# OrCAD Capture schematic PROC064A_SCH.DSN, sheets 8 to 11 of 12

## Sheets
8 09. RGMII ETHERNET PHY 3: size C; title: RGMII ETHERNET PHY 3
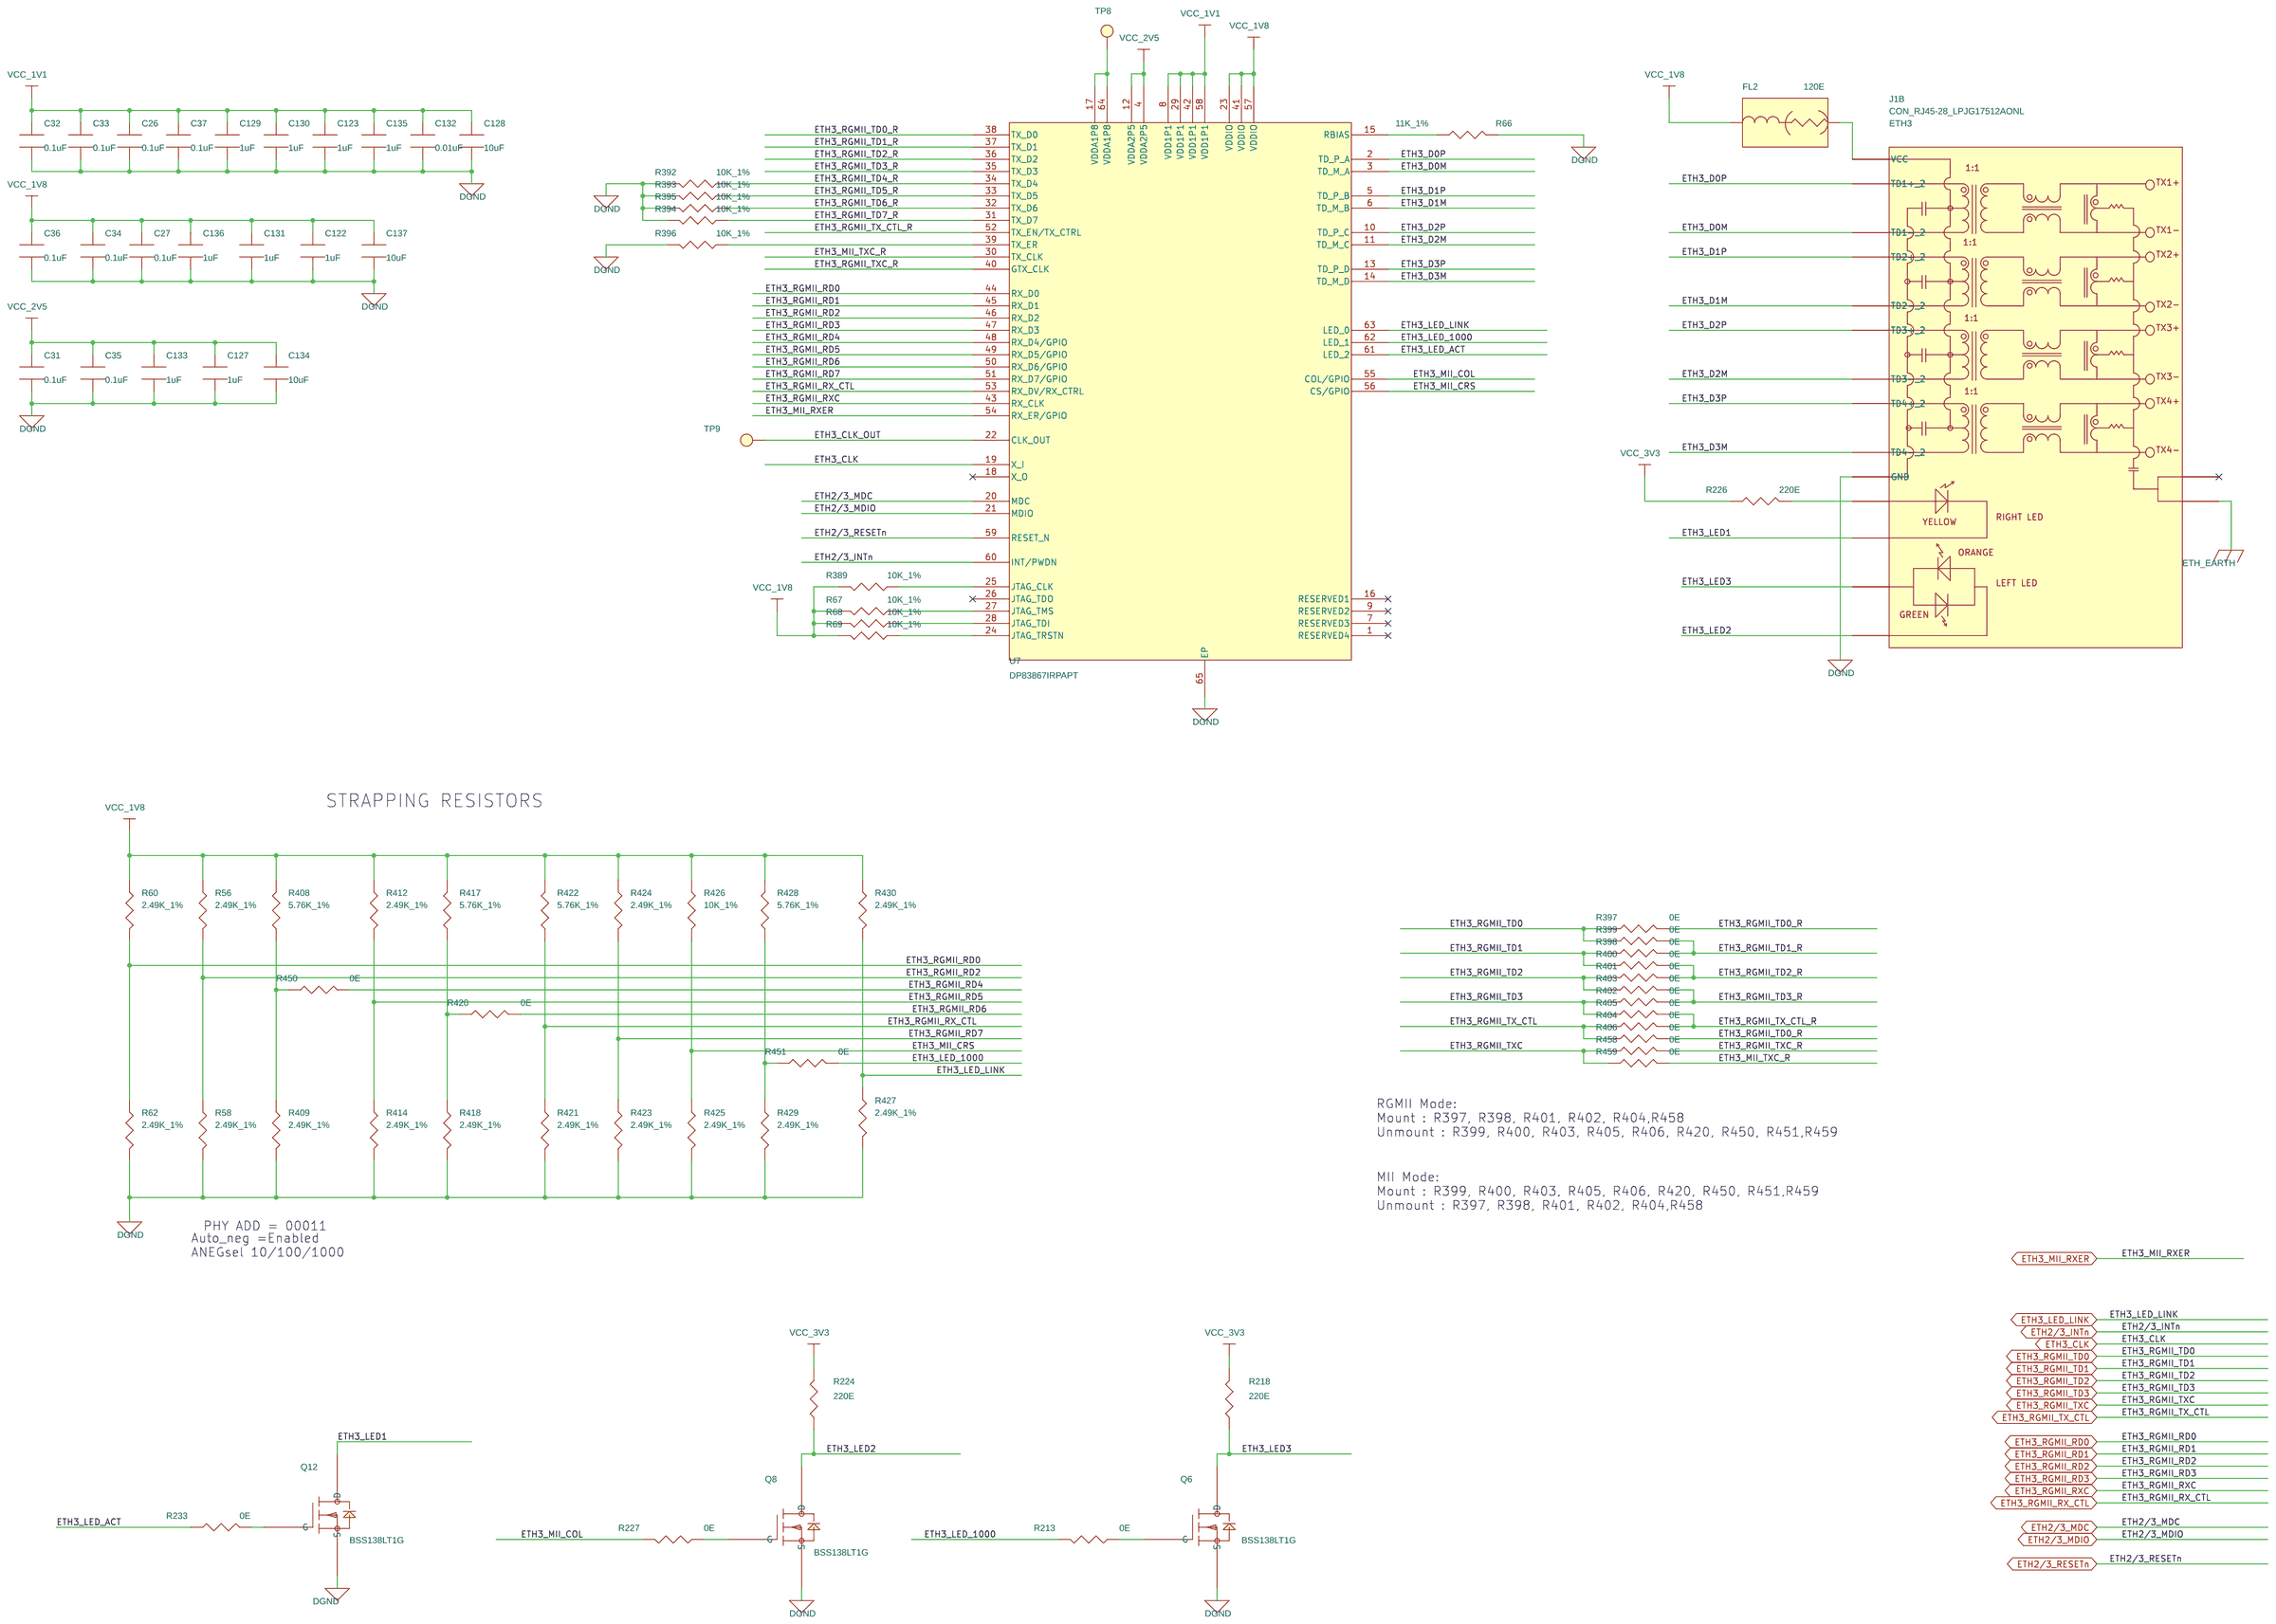
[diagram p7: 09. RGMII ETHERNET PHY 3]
9 10. LED: size C; title: LED
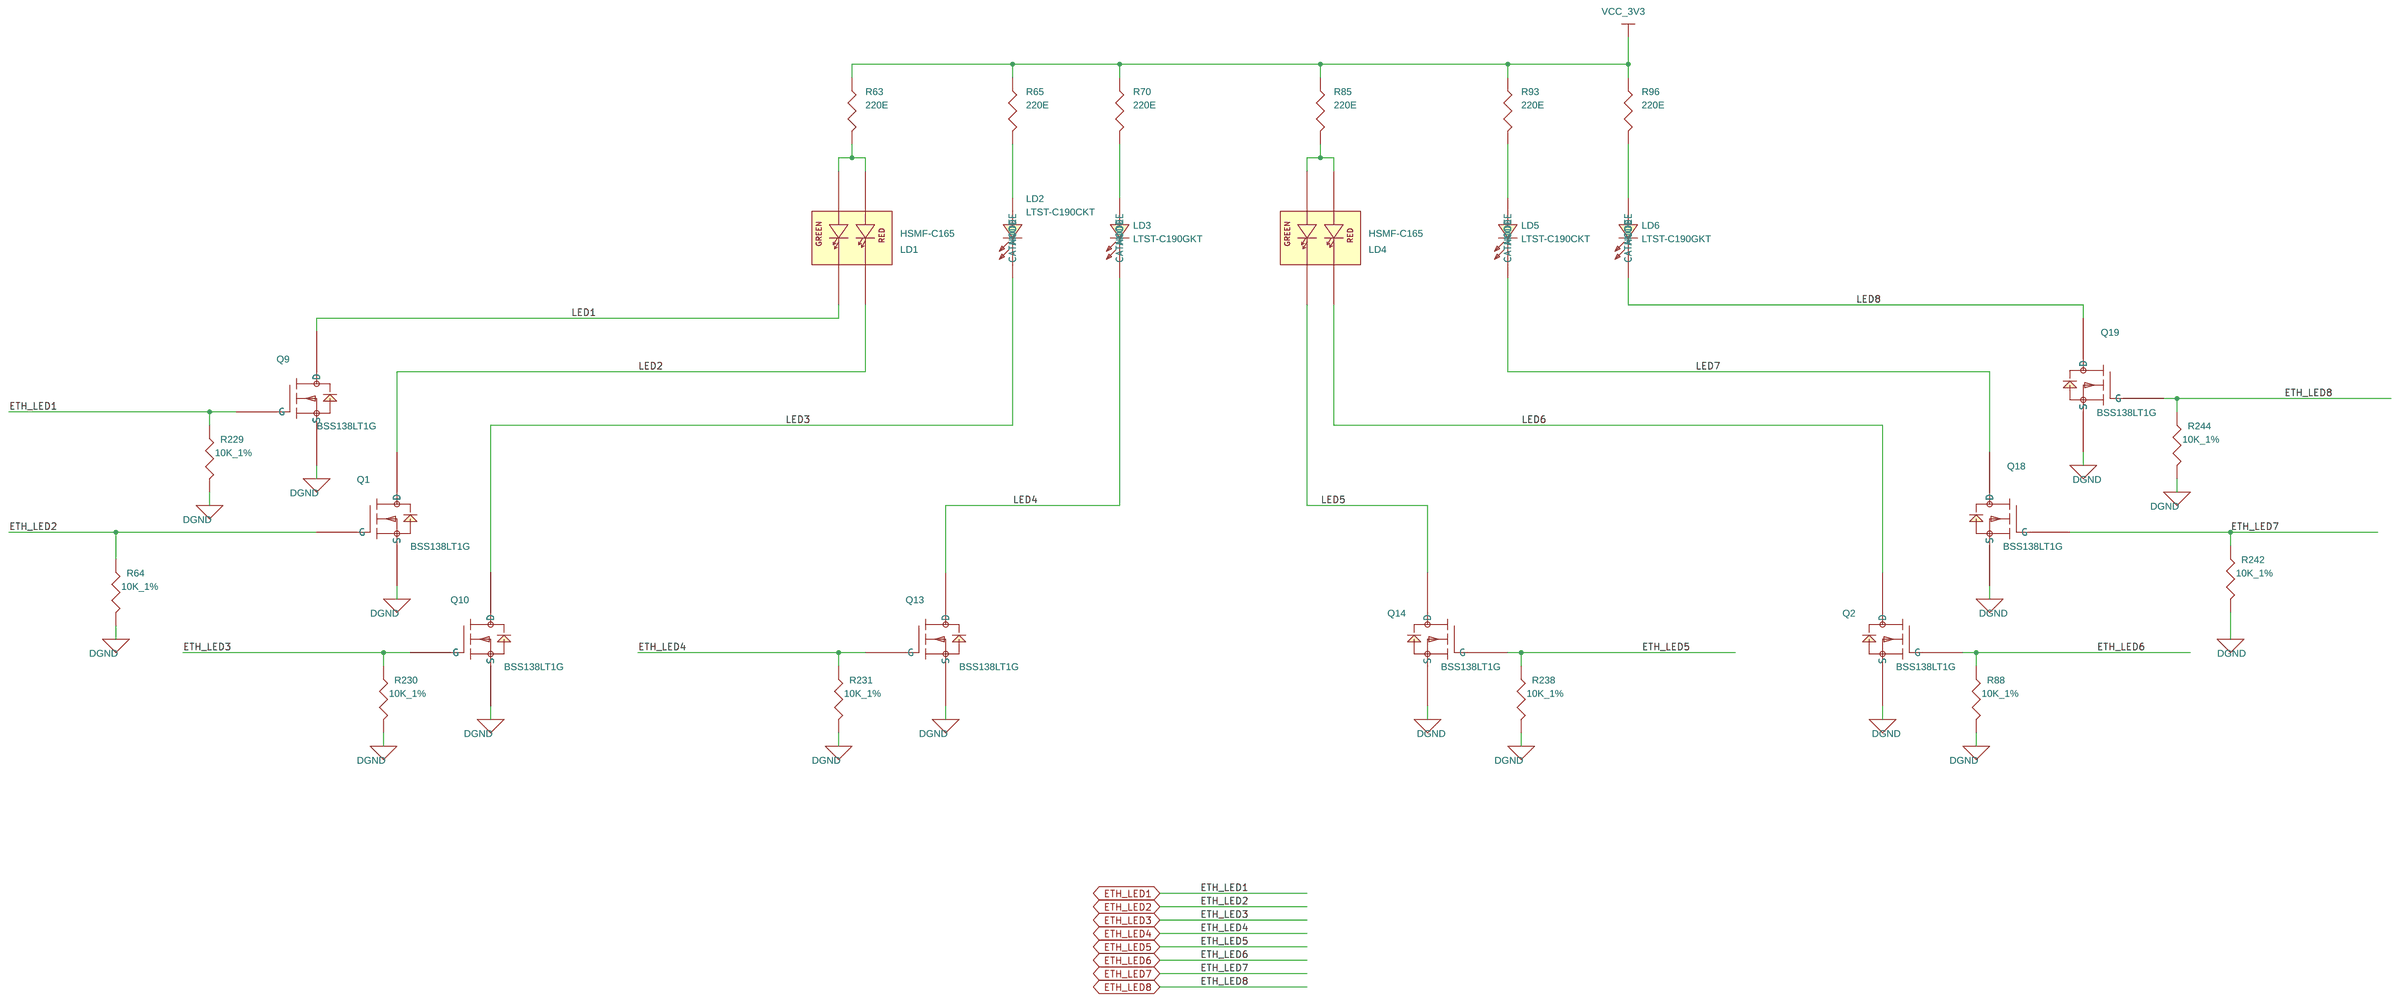
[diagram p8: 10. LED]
10 12. HARDWARE SCHEMATICS: title: HARDWARE SCHEMATICS
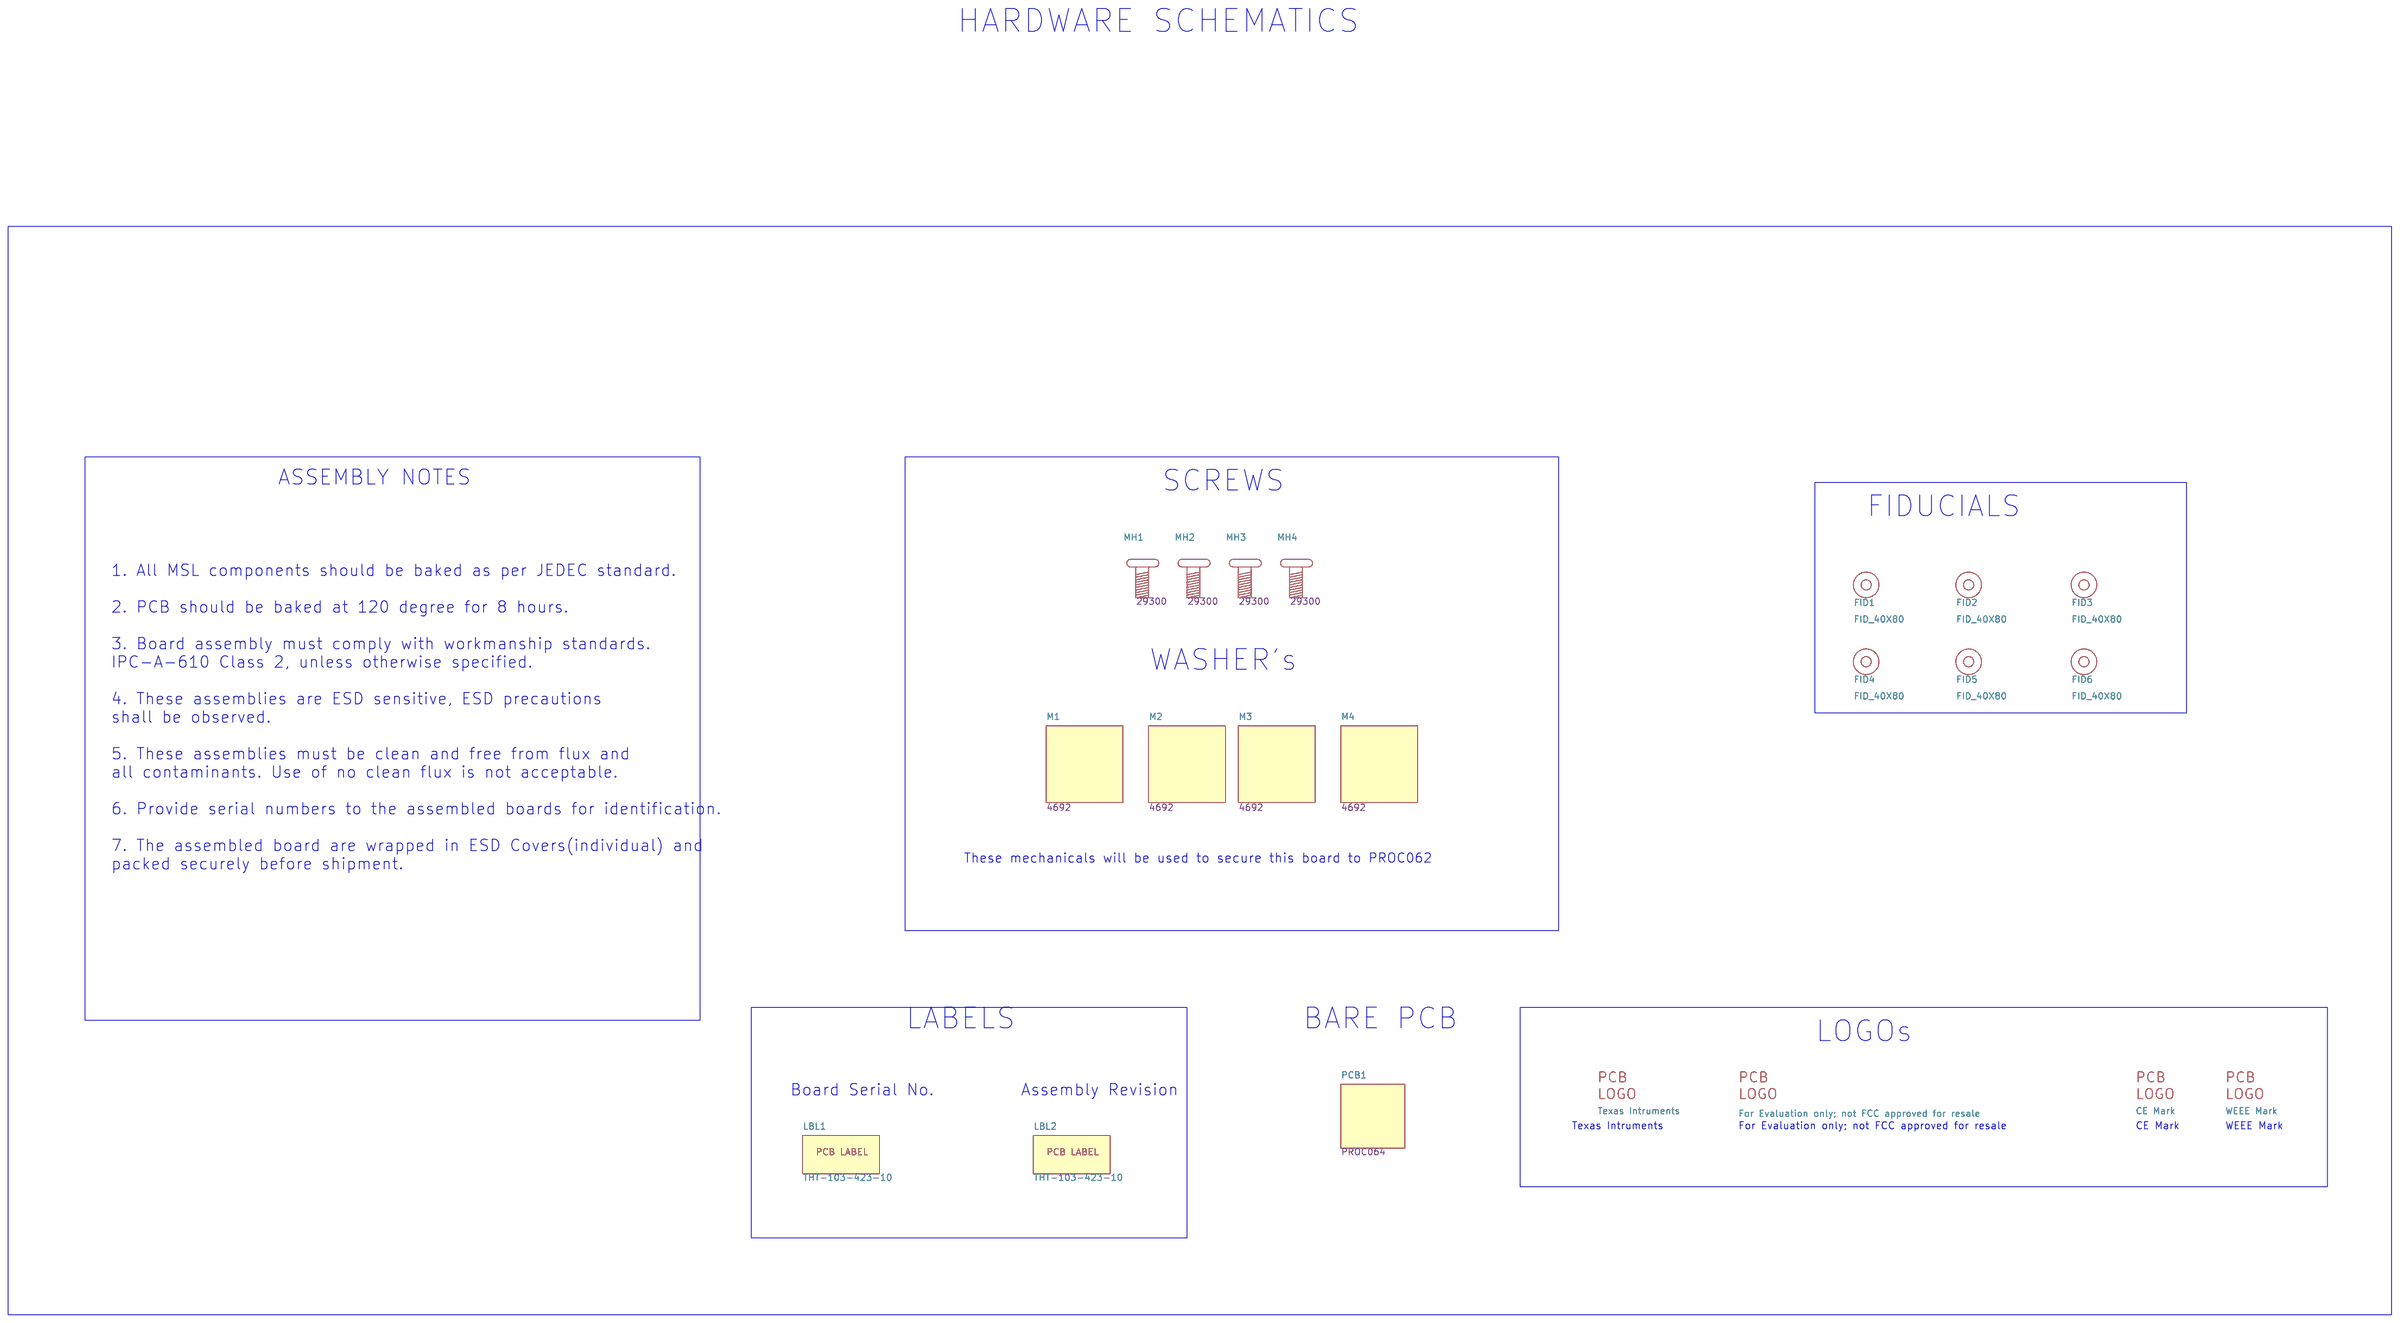
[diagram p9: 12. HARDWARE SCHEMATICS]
11 11. SPI/I2C IOEXPANDER: size C; title: SPI/I2C IOEXPANDER

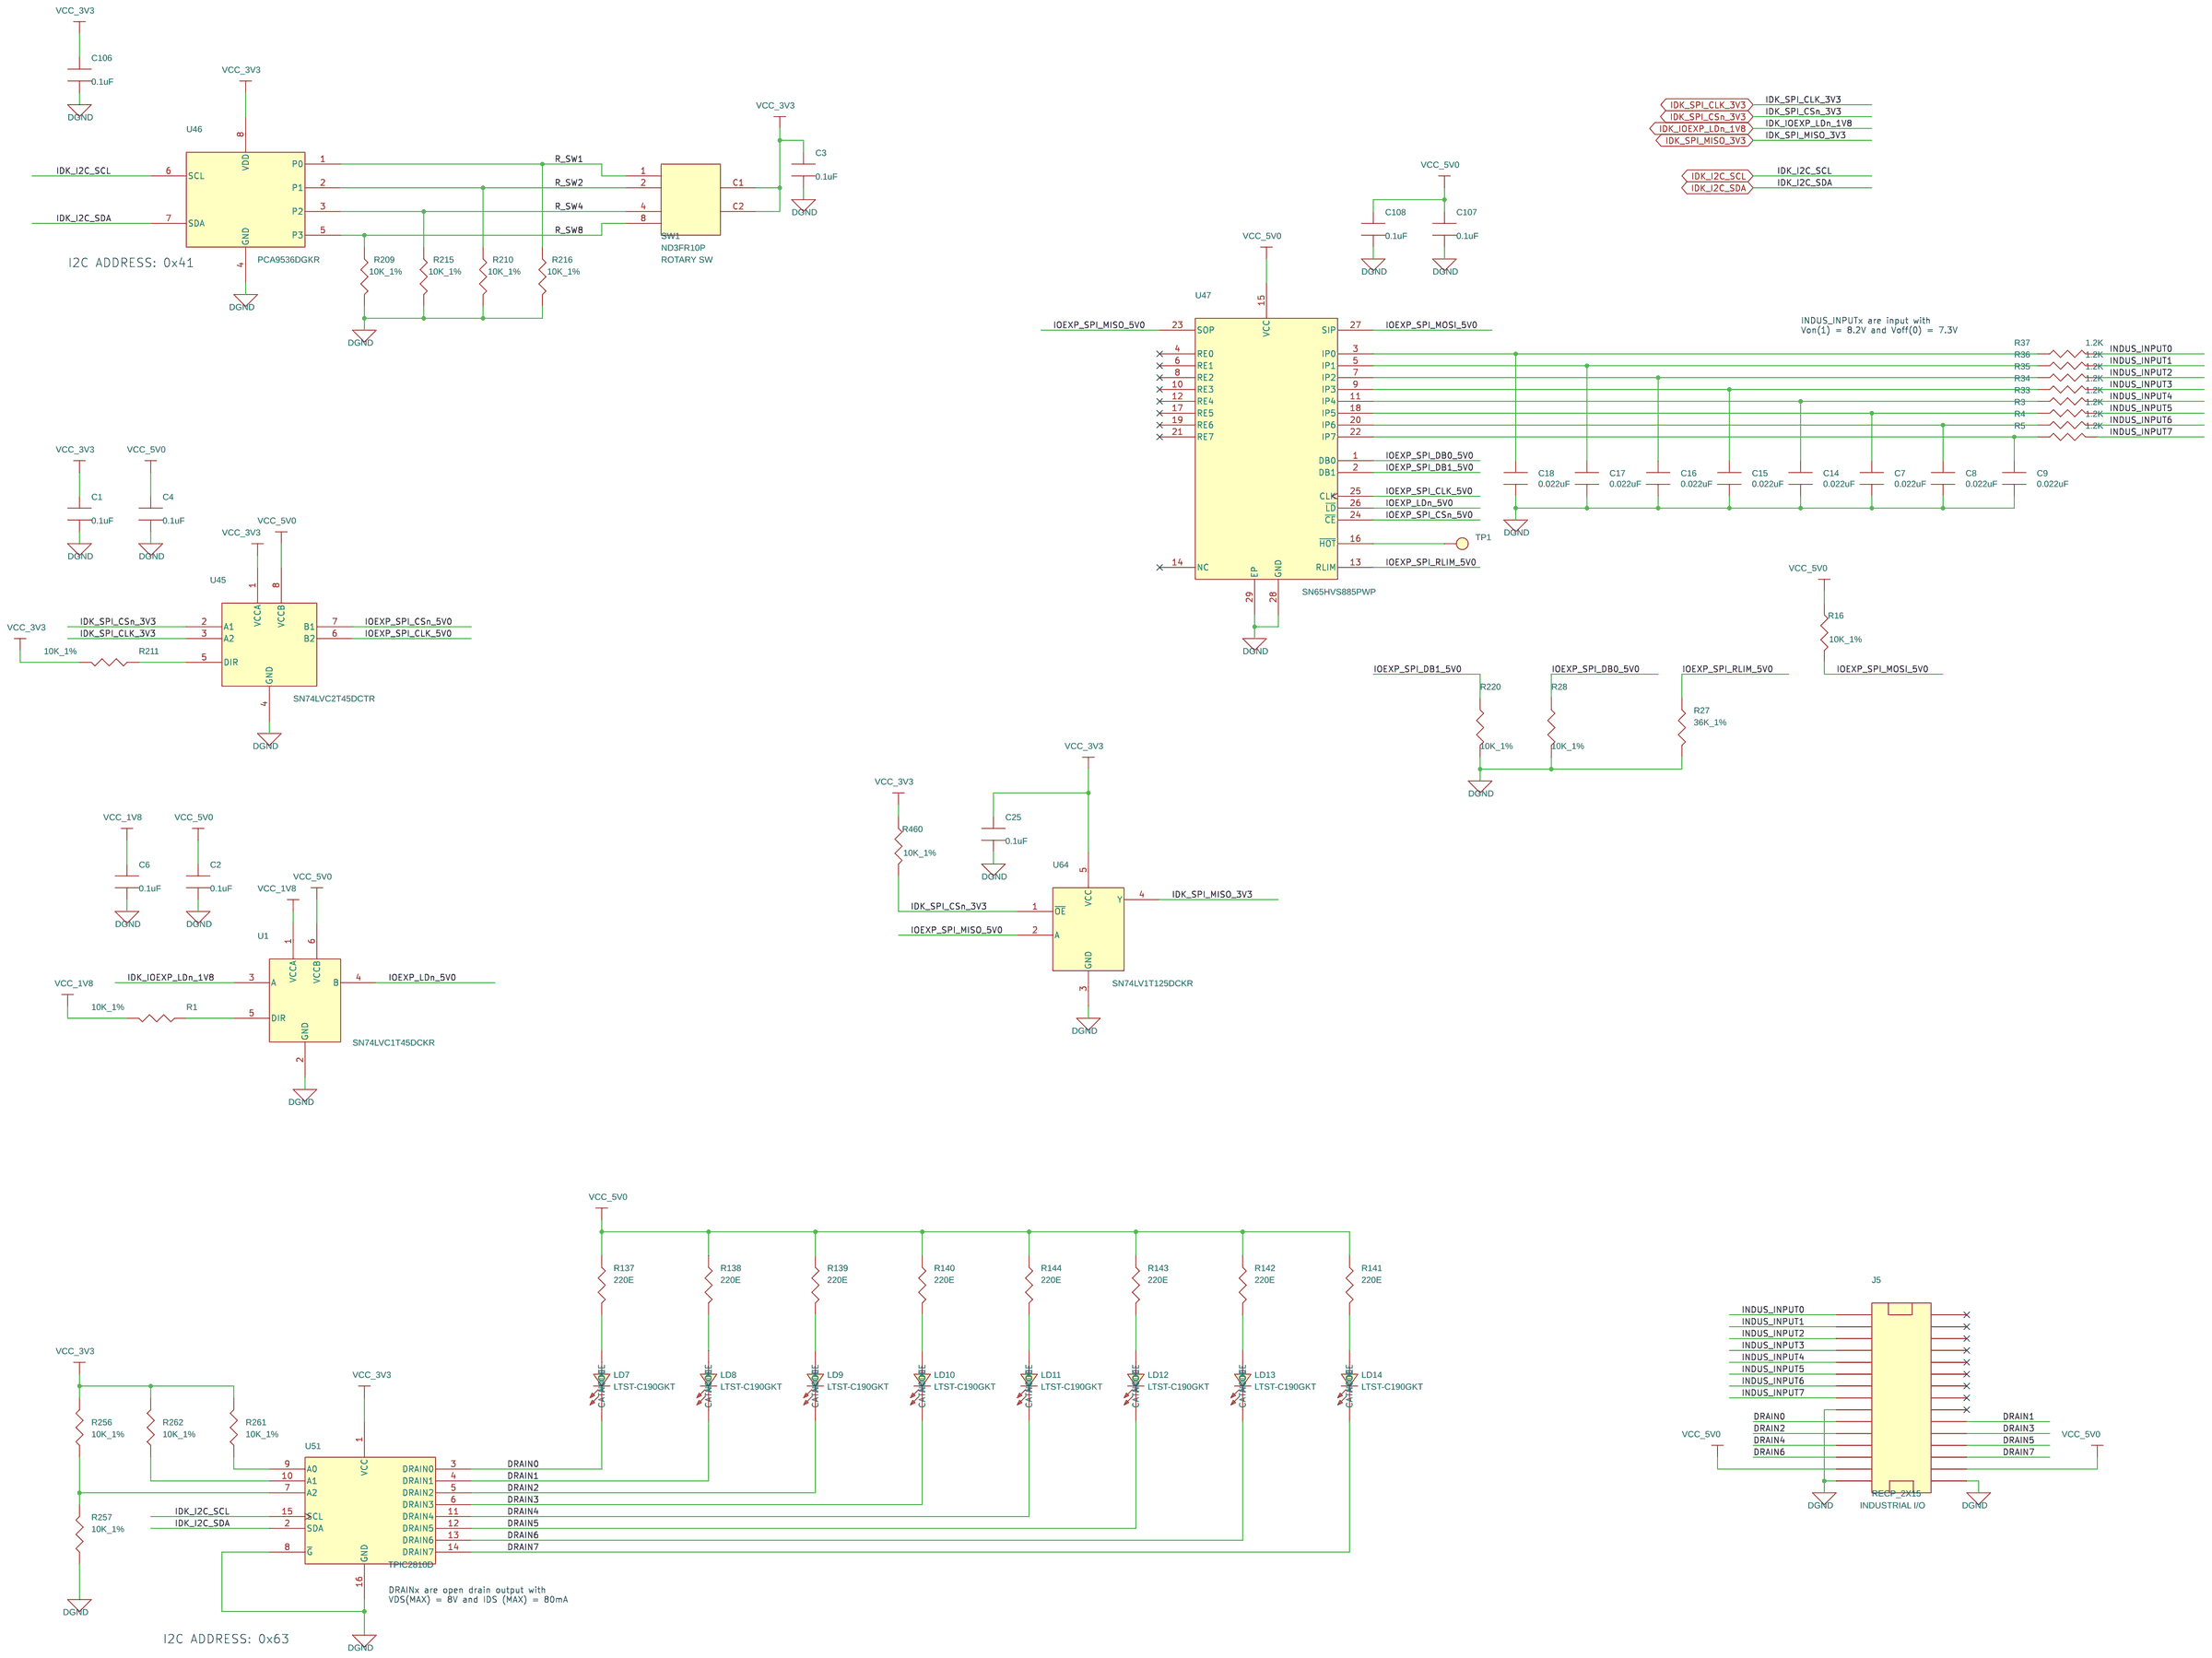
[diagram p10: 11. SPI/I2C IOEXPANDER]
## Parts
sheet 08. RGMII ETHERNET PHY 2
J1  CON_RJ45-28_LPJG17512AONL  [CON_RJ45-28_LPJG17512_S_R_T_25-3]  (sections A,B)
sheet 09. RGMII ETHERNET PHY 3
C26  0.1uF  [CAP0402_0-75]
C27  0.1uF  [CAP0402_0-75]
C31  0.1uF  [CAP0402_0-75]
C32  0.1uF  [CAP0402_0-75]
C33  0.1uF  [CAP0402_0-75]
C34  0.1uF  [CAP0402_0-75]
C35  0.1uF  [CAP0402_0-75]
C36  0.1uF  [CAP0402_0-75]
C37  0.1uF  [CAP0402_0-75]
C122  1uF  [CAP0402_0-75]
C123  1uF  [CAP0402_0-75]
C127  1uF  [CAP0402_0-75]
C128  10uF  [CAP0603_1]
C129  1uF  [CAP0402_0-75]
C130  1uF  [CAP0402_0-75]
C131  1uF  [CAP0402_0-75]
C132  0.01uF  [CAP0402]
C133  1uF  [CAP0402_0-75]
C134  10uF  [CAP0603_1]
C135  1uF  [CAP0402_0-75]
C136  1uF  [CAP0402_0-75]
C137  10uF  [CAP0603_1]
FL2  120E  [EMIFIL_BLM15A_0402_0-6]
Q6  BSS138LT1G  [SOT23-123]
Q8  BSS138LT1G  [SOT23-123]
Q12  BSS138LT1G  [SOT23-123]
R56  2.49K_1%  [RES0402]
R58  2.49K_1%  [RES0402]
R60  2.49K_1%  [RES0402]
R62  2.49K_1%  [RES0402]
R66  11K_1%  [RES0402_0-5]
R67  10K_1%  [RES0402_0-5]
R68  10K_1%  [RES0402_0-5]
R69  10K_1%  [RES0402_0-5]
R213  0E  [RES0402_0-5]
R218  220E  [RES0402_0-5]
R224  220E  [RES0402_0-5]
R226  220E  [RES0402_0-5]
R227  0E  [RES0402_0-5]
R233  0E  [RES0402_0-5]
R389  10K_1%  [RES0402_0-5]
R392  10K_1%  [RES0402_0-5]
R393  10K_1%  [RES0402_0-5]
R394  10K_1%  [RES0402_0-5]
R395  10K_1%  [RES0402_0-5]
R396  10K_1%  [RES0402_0-5]
R397  0E  [RES0402_0-5]
R398  0E  [RES0402_0-5]
R399  0E  [RES0402_0-5]
R400  0E  [RES0402_0-5]
R401  0E  [RES0402_0-5]
R402  0E  [RES0402_0-5]
R403  0E  [RES0402_0-5]
R404  0E  [RES0402_0-5]
R405  0E  [RES0402_0-5]
R406  0E  [RES0402_0-5]
R408  5.76K_1%  [RES0402]
R409  2.49K_1%  [RES0402]
R412  2.49K_1%  [RES0402]
R414  2.49K_1%  [RES0402]
R417  5.76K_1%  [RES0402]
R418  2.49K_1%  [RES0402]
R420  0E  [RES0402_0-5]
R421  2.49K_1%  [RES0402]
R422  5.76K_1%  [RES0402]
R423  2.49K_1%  [RES0402]
R424  2.49K_1%  [RES0402]
R425  2.49K_1%  [RES0402]
R426  10K_1%  [RES0402_0-5]
R427  2.49K_1%  [RES0402]
R428  5.76K_1%  [RES0402]
R429  2.49K_1%  [RES0402]
R430  2.49K_1%  [RES0402]
R450  0E  [RES0402_0-5]
R451  0E  [RES0402_0-5]
R458  0E  [RES0402_0-5]
R459  0E  [RES0402_0-5]
TP8  TP40_SMD  [TP40_SMD]
TP9  TP40_SMD  [TP40_SMD]
U7  DP83867IRPAPT  [EQFP64_19-68_400X400]
sheet 10. LED
LD1  HSMF-C165  [LED4_HSMF-C165_0603_0-5]
LD2  LTST-C190CKT  [LED_0603_0-8]
LD3  LTST-C190GKT  [LED_LTST_0603_0-8]
LD4  HSMF-C165  [LED4_HSMF-C165_0603_0-5]
LD5  LTST-C190CKT  [LED_0603_0-8]
LD6  LTST-C190GKT  [LED_LTST_0603_0-8]
Q1  BSS138LT1G  [SOT23-123]
Q2  BSS138LT1G  [SOT23-123]
Q9  BSS138LT1G  [SOT23-123]
Q10  BSS138LT1G  [SOT23-123]
Q13  BSS138LT1G  [SOT23-123]
Q14  BSS138LT1G  [SOT23-123]
Q18  BSS138LT1G  [SOT23-123]
Q19  BSS138LT1G  [SOT23-123]
R63  220E  [RES0402_0-5]
R64  10K_1%  [RES0402_0-5]
R65  220E  [RES0402_0-5]
R70  220E  [RES0402_0-5]
R85  220E  [RES0402_0-5]
R88  10K_1%  [RES0402_0-5]
R93  220E  [RES0402_0-5]
R96  220E  [RES0402_0-5]
R229  10K_1%  [RES0402_0-5]
R230  10K_1%  [RES0402_0-5]
R231  10K_1%  [RES0402_0-5]
R238  10K_1%  [RES0402_0-5]
R242  10K_1%  [RES0402_0-5]
R244  10K_1%  [RES0402_0-5]
sheet 11. SPI/I2C IOEXPANDER
C1  0.1uF  [CAP0402_0-75]
C2  0.1uF  [CAP0402_0-75]
C3  0.1uF  [CAP0402_0-75]
C4  0.1uF  [CAP0402_0-75]
C6  0.1uF  [CAP0402_0-75]
C7  0.022uF  [CAP0402]
C8  0.022uF  [CAP0402]
C9  0.022uF  [CAP0402]
C14  0.022uF  [CAP0402]
C15  0.022uF  [CAP0402]
C16  0.022uF  [CAP0402]
C17  0.022uF  [CAP0402]
C18  0.022uF  [CAP0402]
C25  0.1uF  [CAP0402_0-75]
C106  0.1uF  [CAP0402_0-75]
C107  0.1uF  [CAP0402_0-75]
C108  0.1uF  [CAP0402_0-75]
J5  RECP_2X15  [RECPT_2X15_66953-015_S_T_8-5]
LD7  LTST-C190GKT  [LED_LTST_0603_0-8]
LD8  LTST-C190GKT  [LED_LTST_0603_0-8]
LD9  LTST-C190GKT  [LED_LTST_0603_0-8]
LD10  LTST-C190GKT  [LED_LTST_0603_0-8]
LD11  LTST-C190GKT  [LED_LTST_0603_0-8]
LD12  LTST-C190GKT  [LED_LTST_0603_0-8]
LD13  LTST-C190GKT  [LED_LTST_0603_0-8]
LD14  LTST-C190GKT  [LED_LTST_0603_0-8]
R1  10K_1%  [RES0402_0-5]
R3  1.2K  [RES0402]
R4  1.2K  [RES0402]
R5  1.2K  [RES0402]
R16  10K_1%  [RES0402_0-5]
R27  36K_1%  [RES0402_0-5]
R28  10K_1%  [RES0402_0-5]
R33  1.2K  [RES0402]
R34  1.2K  [RES0402]
R35  1.2K  [RES0402]
R36  1.2K  [RES0402]
R37  1.2K  [RES0402]
R137  220E  [RES0402_0-5]
R138  220E  [RES0402_0-5]
R139  220E  [RES0402_0-5]
R140  220E  [RES0402_0-5]
R141  220E  [RES0402_0-5]
R142  220E  [RES0402_0-5]
R143  220E  [RES0402_0-5]
R144  220E  [RES0402_0-5]
R209  10K_1%  [RES0402_0-5]
R210  10K_1%  [RES0402_0-5]
R211  10K_1%  [RES0402_0-5]
R215  10K_1%  [RES0402_0-5]
R216  10K_1%  [RES0402_0-5]
R220  10K_1%  [RES0402_0-5]
R256  10K_1%  [RES0402_0-5]
R257  10K_1%  [RES0402_0-5]
R261  10K_1%  [RES0402_0-5]
R262  10K_1%  [RES0402_0-5]
R460  10K_1%  [RES0402_0-5]
SW1  ND3FR10P  [SW10_ND3FR10P_320X300_SMD_5-6]
TP1  TP40_SMD  [TP40_SMD]
U1  SN74LVC1T45DCKR  [SC70-6_1-1]
U45  SN74LVC2T45DCTR  [SSOP8_25-59_120X110]
U46  PCA9536DGKR  [MSOP8_25-59_125X125_1-1]
U47  SN65HVS885PWP  [ETSSOP28_SN65HVS885_390X180_1-2]
U51  TPIC2810D  [SOIC16_1-8]
U64  SN74LV1T125DCKR  [SC70-5_1-1]
sheet 12. HARDWARE SCHEMATICS
FID1  FID_40X80  [FID_40X80]
FID2  FID_40X80  [FID_40X80]
FID3  FID_40X80  [FID_40X80]
FID4  FID_40X80  [FID_40X80]
FID5  FID_40X80  [FID_40X80]
FID6  FID_40X80  [FID_40X80]
LBL1  THT-103-423-10  [NA]
LBL2  THT-103-423-10  [NA]
Logo1  Texas Intruments  [TI_Stacked_Overlay_Small]
Logo2  For Evaluation only; not FCC approved for resale  [FCC_disclaimer]
Logo3  CE Mark  [TI_Stacked_Overlay_Small]
Logo4  WEEE Mark  [TI_Stacked_Overlay_Small]
M1  PLAIN WASHER_M3  [NA]
M2  PLAIN WASHER_M3  [NA]
M3  PLAIN WASHER_M3  [NA]
M4  PLAIN WASHER_M3  [NA]
MH1  PAN HEAD_M2.5 X 4  [NA]
MH2  PAN HEAD_M2.5 X 4  [NA]
MH3  PAN HEAD_M2.5 X 4  [NA]
MH4  PAN HEAD_M2.5 X 4  [NA]
PCB1  AM65x EVM IDK  BARE PCB  [NA]

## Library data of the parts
J1 = CON_RJ45-28_LPJG17512AONL: CON JACK RJ45 28POS REGISTERED FEMALE RA TH; Chkd/date: MANIRAJA/010817; Crtd /date: MANIRAJA/010817; Custom_Duty: 24%; Customs_HS_Code: 85369090; Distributor_name: NA; Distributor_part_number: NA; Height: 25.30MM; Mfr_name: LINK-PP; Mfr_part_number: LPJG17512AONL; Mistral Part No: 150017080001-R; Package: THRU-HOLE; Part_type: CONNECTOR\JACK; Project: TI_SVB_DUT; RoHS: RoHS; TEXT1: ETH2; Temperature: 0°C+70°C; Tolerance: NA; Voltage: NA; Wattage: NA; Weight: NA; Datasheet: Y:\MIS_DATABASE\DATASHEETS\CONNECTORS\LPJG17512AONL.PDF
C1-C4 C6 C25-C27 C31-C37 C106-C108 = CAP: CAP CERAMIC 0.1uF 25V 10% X5R 0402; Chkd/date: MANIRAJA/190220; Crtd /date: ALVY/190220; Custom_Duty: 15%; Customs_HS_Code: 85322990; Distributor_name: DIGIKEY; Distributor_part_number: 311-1697-1-ND; Footprint Path: Y:\MIS_DATABASE\Library\ALTIUM_TOOL\PCB_FOOTPRINTS\Altium_Footprint_Lib.PcbLib; Height: 0.55MM; Library Path: Y:\MIS_DATABASE\Library\ALTIUM_TOOL\SCHEMATICS_PARTS\MS_DISCRETE_Library.schlib; Mfr_name: YAGEO AMERICA; Mfr_part_number: CC0402KRX5R8BB104; Mistral Part No: 120017080016-R; Package: 0402; Part_type: CAPACITORS\CERAMIC; Project: TI_MAXIE_CPB; RoHS: RoHS; Temperature: -55°C+85°C; Tolerance: 10%; Voltage: 25V; Wattage: NA; Weight: 0.65mg; Datasheet: Y:\MIS_DATABASE\DATASHEETS\CAPACITORS\YACC-X5R.PDF
C122 C123 C127 C129-C131 C133 C135 C136 = CAP: CAP CERAMIC 1uF 16V 10% X5R 0402; Chkd/date: MANIRAJA/210817; Crtd /date: MANIRAJA/210817; Custom_Duty: 15%; Customs_HS_Code: 85322990; Distributor_name: DIGIKEY; Distributor_part_number: 587-3709-1-ND; Height: 0.55MM; Mfr_name: TAIYO YUDEN; Mfr_part_number: EMK105BJ105KVHF; Mistral Part No: 120011050002-R; Package: 0402; Part_type: CAPACITORS\CERAMIC; Project: TI_RF_DC CARD; RoHS: RoHS; Temperature: -55°C+85°C; Tolerance: 10%; Voltage: 16V; Wattage: NA; Weight: 0.65mg; Datasheet: Y:\MIS_DATABASE\DATASHEETS\CAPACITORS\EMK105BJ105KVHF.PDF
C128 C134 C137 = CAP: CAP CERAMIC 10uF 25V 20% X5R 0603; Chkd/date: MANIRAJA/130617; Crtd /date: MUDDU/130810; Custom_Duty: 15%; Customs_HS_Code: 85322990; Distributor_name: DIGIKEY; Distributor_part_number: 490-7202-1-ND; Height: 0.90MM; Mfr_name: MURATA; Mfr_part_number: GRM188R61E106MA73D; Mistral Part No: 120010080005-R; Package: 0603; Part_type: CAPACITORS\CERAMIC; Project: PB_BUGBASE; RoHS: RoHS; Temperature: -55°C+85°C; Tolerance: 20%; Voltage: 25V; Wattage: NA; Weight: 6.3mg; Datasheet: Y:\MIS_DATABASE\DATASHEETS\CAPACITORS\MURATA_CMCC.PDF
C132 = CAP: CAP CERAMIC 0.01uF 50V 10% X7R 0402; Alternate_mfr_name_A: MURATA; Alternate_mfr_part_number_A: GRM155R71H103KA88D; Chkd/date: SHREESHAIL/301105; Crtd /date: MAZHAR/040505; Custom_Duty: 15%; Customs_HS_Code: 85322990; Distributor_name: DIGIKEY; Distributor_name_A: DIGIKEY; Distributor_part_number: 399-3066-1-ND; Distributor_part_number_A: 490-4516-1-ND; Height: 0.55MM; Mfr_name: KEMET; Mfr_part_number: C0402C103K5RACTU; Mistral Part No: 120009030025-R; Package: 0402; Part_type: CAPACITORS\CERAMIC; Project: G4_SVGA; RoHS: RoHS; Tolerance: 10%; Voltage: 50V; Datasheet: Y:\MIS_DATABASE\DATASHEETS\CAPACITORS\KEMET-C08.PDF
FL2 = EMIFILTER_IND: FERRITE CHIP 120E 1.3A 0402; Chkd/date: VASANTHA/010117; Crtd /date: CHAITHANYA/150312; Custom_Duty: 24%; Customs_HS_Code: 85437099; Distributor_name: DIGIKEY; Distributor_part_number: 490-5203-1-ND; Footprint Path: Y:\MIS_DATABASE\Library\ALTIUM_TOOL\PCB_FOOTPRINTS\Altium_Footprint_Lib.PcbLib; Height: 0.55MM; Library Path: Y:\MIS_DATABASE\Library\ALTIUM_TOOL\SCHEMATICS_PARTS\MS_FILTER_Library.schlib; Mfr_name: MURATA; Mfr_part_number: BLM15PD121SN1; Mistral Part No: 130012030043-R; Package: 0402; Part_type: MISC\FILTER; Project: GEN_3-8; RoHS: RoHS; Temperature: -55°C+125°C; Tolerance: 25%; Voltage: NA; Wattage: NA; Weight: 0.65mg; Datasheet: Y:\MIS_DATABASE\DATASHEETS\DISCRETES\INDUCTORS\BLM18K-SERIES.PDF
Q1 Q2 Q6 Q8-Q10 Q12-Q14 Q18 Q19 = MOSFET_BSS138LT1G: IC MOSFET N-CHANNEL 50V, SOT23-3; Chkd/date: VASANTHA/150416; Crtd /date: JEBRAN/060416; Custom_Duty: 15%; Customs_HS_Code: 85423100; Distributor_name: MOUSER; Distributor_part_number: 863-BSS138LT1G; Height: 1.11MM; Mfr_name: ON SEMICONDUCTOR; Mistral Part No: 142016040001-R; Package: SOT23-3; Part_type: ICS\POWER\MOSFET; Project: LRDE_ABCM; RoHS: RoHS; Temperature: -55°C+150°C; Tolerance: NA; Voltage: 50V; Wattage: NA; Weight: NA; Datasheet: Y:\MIS_DATABASE\DATASHEETS\DISCRETES\TRANSISTORS_FETS\BSS138LT1G.PDF
R56 R58 R60 R62 R409 R412 R414 R418 R421 R423-R425 R427 R429 R430 = RESISTOR: RES 2.49K 1/16W 1% 0402; Chkd/date: VASANTHA/270516; Crtd /date: VASANTHA/270516; Custom_Duty: 15%; Customs_HS_Code: 85332119; Distributor_name: DIGIKEY; Distributor_part_number: 311-2.49KLRCT-ND; Height: 0.40MM; Mfr_name: YAGEO AMERICA; Mfr_part_number: RC0402FR-072K49L; Mistral Part No: 110016050020-R; Package: 0402; Part_type: RESISTORS\FIXED; Project: TMDXCSKCC; RoHS: RoHS; Temperature: -55°C+155°C; Tolerance: 1%; Voltage: NA; Wattage: 1/16W; Weight: NA; Datasheet: Y:\MIS_DATABASE\DATASHEETS\RESISTORS\RC0402FR.PDF
R66 = RESISTOR: RES 11K 1/16W 1% 0402; Chkd/date: VASANTHA/251115; Crtd /date: VASANTHA/251115; Custom_Duty: 15%; Customs_HS_Code: 85332119; Distributor_name: DIGIKEY; Distributor_part_number: 311-11.0KLRCT-ND; Height: 0.40MM; Mfr_name: YAGEO AMERICA; Mfr_part_number: RC0402FR-0711KL; Mistral Part No: 110015110012-P; Package: 0402; Part_type: RESISTORS\FIXED; Project: TI_VLAN_SWITCH; RoHS: Pb-Free; Temperature: -55°C+155°C; Tolerance: 1%; Voltage: NA; Wattage: 1/16W; Weight: 0.65mg; Datasheet: Y:\MIS_DATABASE\DATASHEETS\RESISTORS\YAGEO-RC0402.PDF
R1 R16 R28 R64 R67-R69 R88 R209-R211 R215 R216 R220 R229-R231 R238 R242 R244 R256 R257 R261 R262 R389 R392-R396 R426 R460 = RESISTOR: RES 10K 1/16W 1% 0402; Chkd/date: VASANTHA/201216; Crtd /date: GEETHA/290506; Custom_Duty: 15%; Customs_HS_Code: 85332119; Distributor_name: DIGIKEY; Distributor_part_number: 311-10.0KLRTR-ND; Footprint Path: Y:\MIS_DATABASE\Library\ALTIUM_TOOL\PCB_FOOTPRINTS\Altium_Footprint_Lib.PcbLib; Height: 0.40MM; Library Path: Y:\MIS_DATABASE\Library\ALTIUM_TOOL\SCHEMATICS_PARTS\MS_DISCRETE_Library.schlib; Mfr_name: YAGEO AMERICA; Mfr_part_number: RC0402FR-0710KL; Mistral Part No: 110009030220-P; Package: 0402; Part_type: RESISTORS\FIXED; Project: VOCERA; RoHS: Pb-Free; Temperature: -55°C+155°C; Tolerance: 1%; Voltage: NA; Wattage: 1/16W; Weight: 0.65mg; Datasheet: Y:\MIS_DATABASE\DATASHEETS\RESISTORS\YAGEO-RC0402.PDF
R213 R227 R233 R397-R406 R420 R450 R451 R458 R459 = RESISTOR: RES 0E 1/16W 0402; Chkd/date: VASANTHA/201216; Crtd /date: MUDDU/190810; Custom_Duty: 15%; Customs_HS_Code: 85332119; Distributor_name: DIGIKEY; Distributor_part_number: 541-0.0JCT-ND; Footprint Path: Y:\MIS_DATABASE\Library\ALTIUM_TOOL\PCB_FOOTPRINTS\Altium_Footprint_Lib.PcbLib; Height: 0.40MM; Library Path: Y:\MIS_DATABASE\Library\ALTIUM_TOOL\SCHEMATICS_PARTS\MS_DISCRETE_Library.schlib; Mfr_name: VISHAY; Mfr_part_number: CRCW04020000Z0ED; Mistral Part No: 110010080019-P; Package: 0402; Part_type: RESISTORS\FIXED; Project: PB_BUGBASE; RoHS: Pb-Free; Temperature: -55°C+155°C; Tolerance: NA; Voltage: NA; Wattage: 1/16W; Weight: 0.65g/1000pcs; Datasheet: Y:\MIS_DATABASE\DATASHEETS\RESISTORS\CRCW0603.PDF
R63 R65 R70 R85 R93 R96 R137-R144 R218 R224 R226 = RESISTOR: RES 220E 1/16W 5% 0402; Chkd/date: VASANTHA/291216; Crtd /date: GEETHA/260406; Custom_Duty: 15%; Customs_HS_Code: 85332119; Distributor_name: DIGIKEY; Distributor_part_number: P220JCT-ND; Footprint Path: Y:\MIS_DATABASE\Library\ALTIUM_TOOL\PCB_FOOTPRINTS\Altium_Footprint_Lib.PcbLib; Height: 0.40MM; Library Path: Y:\MIS_DATABASE\Library\ALTIUM_TOOL\SCHEMATICS_PARTS\MS_DISCRETE_Library.schlib; Mfr_name: PANASONIC-ECG; Mfr_part_number: ERJ-2GEJ221X; Mistral Part No: 110009030506-R; Package: 0402; Part_type: RESISTORS\FIXED; Project: RED EYE; RoHS: RoHS; Temperature: -55°C+155°C; Tolerance: 5%; Voltage: NA; Wattage: 1/16W; Weight: 0.8g/1000pcs; Datasheet: Y:\MIS_DATABASE\DATASHEETS\RESISTORS\ERJ12.PDF
R408 R417 R422 R428 = RESISTOR: RES 5.76K 1/10W 1% 0402; Chkd/date: MAZHAR/150709; Crtd /date: USMAN/220808; Custom_Duty: 15%; Customs_HS_Code: 85332119; Distributor_name: DIGIKEY; Distributor_part_number: P5.76KLCT-ND; Footprint Path: Y:\MIS_DATABASE\Library\ALTIUM_TOOL\PCB_FOOTPRINTS\Altium_Footprint_Lib.PcbLib; Height: 0.40MM; Library Path: Y:\MIS_DATABASE\Library\ALTIUM_TOOL\SCHEMATICS_PARTS\MS_DISCRETE_Library.schlib; Mfr_name: PANASONIC-ECG; Mfr_part_number: ERJ-2RKF5761X; Mistral Part No: 110009030945-R; Package: 0402; Part_type: RESISTORS\FIXED; Project: CPB; RoHS: RoHS; Tolerance: 1%; Wattage: 1/10W; Datasheet: Y:\MIS_DATABASE\DATASHEETS\RESISTORS\PAN-ERJSERIES.PDF
TP1 TP8 TP9 = TESTPOINT: TESTPOINT CIR 40 SMD; Chkd/date: MAZHAR/190505; Crtd /date: MAZHAR/190505; Distributor_name: NA; Distributor_part_number: NA; Footprint Path: Y:\MIS_DATABASE\Library\ALTIUM_TOOL\PCB_FOOTPRINTS\Altium_Footprint_Lib.PcbLib; Height: NA; Library Path: Y:\MIS_DATABASE\Library\ALTIUM_TOOL\SCHEMATICS_PARTS\MS_DISCRETE_Library.schlib; MECHANICAL 3D STEP FILE: NA; Mfr_name: LOCAL; Mistral Part No: 130009030933; Package: SMD; Project: RAINIER-3; RoHS: NA; Temperature: NA; Tolerance: NA; Voltage: NA; Wattage: NA; Weight: NA; Datasheet: NA
U7 = DP83867IRPAPT_HTQFP64: IC HIGH IMMUNITY 10/100/1000 Mb/s ETHERNET PHY LAYER TRANSCEIVER HTQFP64; Chkd/date: VASANTHA/250516; Crtd /date: VASANTHA/250516; Custom_Duty: 15%; Customs_HS_Code: 85423100; Distributor_name: DIGIKEY; Distributor_part_number: 296-41117-1-ND; Height: 1.20MM; Mfr_name: TEXAS INSTRUMENTS; Mistral Part No: 143016050002-R; Package: HTQFP64; Part_type: ICS\TELECOM\TRANSCEIVER; Project: TMDXCSKCC; RoHS: RoHS; Temperature: -40°C+85°C; Tolerance: NA; Voltage: NA; Wattage: NA; Weight: NA; Datasheet: Y:\MIS_DATABASE\DATASHEETS\ICS\DIGITAL\BUSTRANSCEIVER\DP83867I.PDF
LD1 LD4 = LED4_HSMF-C165: DIODE LED RED AND GREEN 0603; Chkd/date: MANIRAJA/301017; Crtd /date: MANIRAJA/301017; Custom_Duty: 24%; Customs_HS_Code: 85439000; Distributor_name: DIGIKEY; Distributor_part_number: 516-1419-1-ND; Height: 0.50MM; Mfr_name: AVAGO TECH; Mistral Part No: 130017100033-R; Package: 0603; Part_type: OPTO\LED; Project: TI_MAXIE_CPB; RoHS: RoHS; Temperature: -40°C+85°C; Tolerance: NA; Voltage: NA; Wattage: NA; Weight: NA; Datasheet: Y:\MIS_DATABASE\DATASHEETS\DISCRETES\LEDS\HSMF-C16X.PDF
LD2 LD5 = DIODE_LED: DIODE LED RED 0603; Chkd/date: VASANTHA/281216; Crtd /date: MAZHAR/050808; Custom_Duty: 24%; Customs_HS_Code: 85439000; Distributor_name: DIGIKEY; Distributor_part_number: 160-1181-1-ND; Height: 0.80MM; Mfr_name: LITEON; Mistral Part No: 130009031018-R; Package: 0603; Part_type: OPTO\LED; Project: REVA-IBMS; RoHS: RoHS; Temperature: -55°C+85°C; Tolerance: NA; Voltage: NA; Wattage: NA; Weight: NA; Datasheet: Y:\MIS_DATABASE\DATASHEETS\DISCRETES\LEDS\LTST-C190CKT.PDF
LD3 LD6-LD14 = DIODE_LED: DIODE LED GREEN 0603; Chkd/date: VASANTHA/201216; Crtd /date: MAZHAR/290807; Custom_Duty: 24%; Customs_HS_Code: 85439000; Distributor_name: DIGIKEY; Distributor_part_number: 160-1183-1-ND; Height: 0.80MM; Mfr_name: LITEON; Mistral Part No: 130009031020-R; Package: 0603; Part_type: OPTO\LED; Project: MARP; RoHS: RoHS; Temperature: -55°C+85°C; Tolerance: NA; Voltage: NA; Wattage: NA; Weight: NA; Datasheet: Y:\MIS_DATABASE\DATASHEETS\DISCRETES\LEDS\LTST-C190GKT.PDF
C7-C9 C14-C18 = CAP: CAP CERAMIC 0.022uF 50V 10% X7R 0402; Chkd/date: MAZHAR/301208; Crtd /date: USMAN/051108; Custom_Duty: 15%; Customs_HS_Code: 85322990; Distributor_name: DIGIKEY; Distributor_part_number: 490-4763-1-ND; Height: 0.55MM; Mfr_name: MURATA; Mfr_part_number: GCM155R71H223KA55D; Mistral Part No: 120009030036-R; Package: 0402; Part_type: CAPACITORS\CERAMIC; Project: P2ER6DB; RoHS: RoHS; Tolerance: 10%; Voltage: 50V; Datasheet: Y:\MIS_DATABASE\DATASHEETS\CAPACITORS\GCM155R71H223KA55.PDF
J5 = RECP_15X2: CON RECP 2X15 2.54MM PITCH ST TH; Chkd/date: MANIRAJA/280817; Crtd /date: MANIRAJA/280817; Custom_Duty: 24%; Customs_HS_Code: 85369090; Distributor_name: DIGIKEY; Distributor_part_number: 609-2279-ND; Height: 8.50MM; Mfr_name: FCI; Mfr_part_number: 66953-015LF; Mistral Part No: 150017080021-R; Package: THRU-HOLE; Part_type: CONNECTOR\RECEPTACLE; Project: TI_MAXIE_CPB; RoHS: RoHS; TEXT: INDUSTRIAL I/O; Temperature: -65°C+125°C; Tolerance: NA; Voltage: NA; Wattage: NA; Weight: NA; Datasheet: Y:\MIS_DATABASE\DATASHEETS\CONNECTORS\66953_SERIES.PDF
R3-R5 R33-R37 = RESISTOR: RES 1.2K 1/10W 5% 0402; Chkd/date: USMAN/050312; Crtd /date: CHAITHANYA/050312; Custom_Duty: 15%; Customs_HS_Code: 85332119; Distributor_name: DIGIKEY; Distributor_part_number: P1.2KJCT-ND; Height: 0.40MM; Mfr_name: PANASONIC; Mfr_part_number: ERJ-2GEJ122X; Mistral Part No: 110012020015-R; Package: 0402; Part_type: RESISTORS\FIXED; Project: IP_CAMERA; RoHS: RoHS; Temperature: -55°C+155°C; Tolerance: 5%; Voltage: NA; Wattage: 1/10W; Weight: 0.8/1000g; Datasheet: Y:\MIS_DATABASE\DATASHEETS\RESISTORS\ERJ2G.PDF
R27 = RESISTOR: RES 36K 1/16W 1% 0402; Chkd/date: MANIRAJA/140218; Crtd /date: ALVY/130218; Custom_Duty: 15%; Customs_HS_Code: 85332119; Distributor_name: DIGIKEY; Distributor_part_number: 311-36.0KLRCT-ND; Footprint Path: Y:\MIS_DATABASE\Library\ALTIUM_TOOL\PCB_FOOTPRINTS\Altium_Footprint_Lib.PcbLib; Height: 0.40MM; Library Path: Y:\MIS_DATABASE\Library\ALTIUM_TOOL\SCHEMATICS_PARTS\MS_DISCRETE_Library.schlib; Mfr_name: YAGEO AMERICA; Mfr_part_number: RC0402FR-0736KL; Mistral Part No: 110018020006-R; Package: 0402; Part_type: RESISTORS\FIXED; Project: GRYPHON; RoHS: RoHS; Temperature: -55°C+155°C; Tolerance: 1%; Voltage: NA; Wattage: 1/16W; Weight: 0.65mg; Datasheet: Y:\MIS_DATABASE\DATASHEETS\RESISTORS\YAGEO-RC0402.PDF
SW1 = SW10_ND3FR10P: SWITCH DIP ROTARY TOOL ACTUATOR 10POS SMD; Chkd/date: MANIRAJA/280817; Crtd /date: MANIRAJA/280817; Custom_Duty: 24%; Customs_HS_Code: 85369090; Distributor_name: DIGIKEY; Distributor_part_number: ND3FR10P-ND; Height: 5.60MM; Mfr_name: NKK; Mistral Part No: 130017080030-R; Package: SMD; Part_type: ELECTRO-MECHANICAL\SWITCH; Project: TI_MAXIE_CPB; RoHS: RoHS; TEXT: ROTARY SW; Temperature: -25°C+85°C; Tolerance: NA; Voltage: NA; Wattage: NA; Weight: NA; Datasheet: Y:\MIS_DATABASE\DATASHEETS\MISC\SWITCHES\NKK-ND3-SER.PDF
U1 = SN74LVC1T45DCKR_SC70-6: IC BUS TRANSCEIVER TRI-STATE SC70-6; Chkd/date: VASANTHA/221216; Crtd /date: MUDDU/180510; Custom_Duty: 15%; Customs_HS_Code: 85423100; Distributor_name: DIGIKEY; Distributor_part_number: 296-16844-1-ND; Height: 1.10MM; Mfr_name: TEXAS INSTRUMENTS; Mistral Part No: 141010050007-R; Package: SC70-6; Part_type: ICS\DIGITAL\COMBINATIONAL; Project: ICD_DFS; RoHS: Sb/ Br FREE; Temperature: -40°C+85°C; Tolerance: NA; Voltage: NA; Wattage: NA; Weight: 2.5mg; Datasheet: Y:\MIS_DATABASE\DATASHEETS\ICS\DIGITAL\BUSTRANSCEIVER\SN74LVC1T45DCKR.PDF
U45 = SN74LVC2T45DCTR_SM8-8: IC DUAL BIT DUAL-SUPPLY BUS TRANSCEIVER SM8-8; Chkd/date: NAVEED/300715; Crtd /date: MUDDU/240310; Custom_Duty: 15%; Customs_HS_Code: 85423100; Distributor_name: DIGIKEY; Distributor_part_number: 296-16845-1-ND; Height: 1.30MM; Mfr_name: TEXAS INSTRUMENTS; Mistral Part No: 143010030001-P; Package: SM8-8; Part_type: ICS\TELECOM\TRANSCEIVER; Project: GEACOM_PHRAZER; RoHS: Pb-Free; Temperature: -40°C+85°C; Weight: NA; Datasheet: Y:\MIS_DATABASE\DATASHEETS\ICS\DIGITAL\BUSTRANSCEIVER\SN74LVC2T45DCTR.PDF
U46 = PCA9536DR_SOIC8: IC 4-BIT I2C AND SMBUS I/O EXPANDER MSOP8; Chkd/date: MANIRAJA/180917; Crtd /date: MANIRAJA/180917; Custom_Duty: 15%; Customs_HS_Code: 85423100; Distributor_name: DIGIKEY; Distributor_part_number: 296-20952-1-ND; Height: 1.10MM; Mfr_name: TEXAS INSTRUMENTS; Mistral Part No: 141017090015-R; Package: MSOP8; Part_type: ICS\DIGITAL\BUSTRANSCEIVER; Project: TI_MAXIE_CPB; RoHS: RoHS; Temperature: -40°C+85°C; Tolerance: NA; Voltage: NA; Wattage: NA; Weight: 19mg; Datasheet: Y:\MIS_DATABASE\DATASHEETS\ICS\DIGITAL\BUSTRANSCEIVER\PCA95.PDF
U47 = SN65HVS885PWP_HTSSOP28: IC 5V DIGITAL I/P SERIALIZER HTSSOP28; Chkd/date: MANIRAJA/111017; Crtd /date: MANIRAJA/111017; Custom_Duty: 15%; Customs_HS_Code: 85423100; Distributor_name: DIGIKEY; Distributor_part_number: 296-24167-5-ND; Height: 1.20MM; Mfr_name: TEXAS INSTRUMENTS; Mistral Part No: 141017100007-R; Package: HTSSOP28; Part_type: ICS\INTERFACE; Project: TI_MAXIE_CPB; RoHS: RoHS; Temperature: -40°C+125°C; Tolerance: NA; Voltage: NA; Wattage: NA; Weight: 118.5mg; Datasheet: Y:\MIS_DATABASE\DATASHEETS\ICS\INTERFACE\SN65HVS885.PDF
U51 = TPIC2810D_SOIC16: IC 8-BIT LED DRIVER WITH I2C INTERFACE SOIC16; Chkd/date: MANIRAJA/230817; Crtd /date: MANIRAJA/220817; Custom_Duty: 15%; Customs_HS_Code: 85423100; Distributor_name: DIGIKEY; Distributor_part_number: 296-13746-5-ND; Height: 1.75MM; Mfr_name: TEXAS INSTRUMENTS; Mistral Part No: 141017080026-R; Package: SOIC16; Part_type: ICS\INTERFACE; Project: TI_MAXIE_CPB; RoHS: RoHS; Temperature: -40°C+125°C; Tolerance: NA; Voltage: NA; Wattage: NA; Weight: NA; Datasheet: Y:\MIS_DATABASE\DATASHEETS\ICS\INTERFACE\TPIC2810D.PDF
U64 = SN74LV1T125DCKR_SC70-5: IC BUFFER GATE 3-STATE O/P CMOS LEVEL SHIFTER SC70-5; Chkd/date: VASANTHA/101214; Crtd /date: NAVEED/020914; Custom_Duty: 15%; Customs_HS_Code: 85423100; Distributor_name: DIGIKEY; Distributor_part_number: 296-37173-1-ND; Height: 1.10MM; Mfr_name: TEXAS INSTRUMENTS; Mistral Part No: 141014090004-R; Package: SC70-5; Part_type: ICS\DIGITAL\COMBINATIONAL; Project: DARE_DIO; RoHS: RoHS; Temperature: -40°C+125°C; Tolerance: NA; Voltage: NA; Wattage: NA; Weight: NA; Datasheet: Y:\MIS_DATABASE\DATASHEETS\ICS\DIGITAL\COMBINATIONAL\SN74LV1T125D.PDF
FID1-FID6 = Fiducial
LBL1 LBL2 = ACCESSORY_THT-3-423-10: ACCESSORIE 1 WORKHORSE POLYSTER LABLE 0.25" X 1"; Chkd/date: MANIRAJA/270218; Crtd /date: ALVY/260218; Footprint Path: Y:\MIS_DATABASE\Library\ALTIUM_TOOL\PCB_FOOTPRINTS\Altium_Footprint_Lib.PcbLib; Library Path: Y:\MIS_DATABASE\Library\ALTIUM_TOOL\SCHEMATICS_PARTS\MS_MECHANICAL_Library.schlib; Mfr_name: BRADY; Mistral Part No: 160018020185; Part_type: ACCESSORIES; Project: TI_MAXIE_CPB
Logo1 Logo3 Logo4 = TI_Logo
Logo2 = FCC_disclaimer
M1-M4 = WASHER_PLAIN: PLAIN WASHER FOR M3 SS-316; Chkd/date: MANIRAJA/190218; Crtd /date: MANIRAJA/190218; Distributor_name: DIGIKEY; Distributor_part_number: 36-4692-ND; Footprint Path: Y:\MIS_DATABASE\Library\ALTIUM_TOOL\PCB_FOOTPRINTS\Altium_Footprint_Lib.PcbLib; Library Path: Y:\MIS_DATABASE\Library\ALTIUM_TOOL\SCHEMATICS_PARTS\MS_MECHANICAL_Library.schlib; Mfr_name: KEYSTONE; Mfr_part_number: 4692; Mistral Part No: 160018020078-R; Package: SS; Part_type: MECHANICAL\WASHERS; Project: TI_MAXIE_CPB; RoHS: RoHS; Datasheet: Y:\MIS_DATABASE\DATASHEETS\MISC\MECHANICAL\4692.PDF
MH1-MH4 = SCREW_PAN: PHILLIPS PAN HEAD SCREW - M2.5 X 4 SS-316; Chkd/date: MANIRAJA/190218; Crtd /date: MANIRAJA/190218; Distributor_name: DIGIKEY; Distributor_part_number: 36-29300-ND; Footprint Path: Y:\MIS_DATABASE\Library\ALTIUM_TOOL\PCB_FOOTPRINTS\Altium_Footprint_Lib.PcbLib; Height: 4.00MM; Library Path: Y:\MIS_DATABASE\Library\ALTIUM_TOOL\SCHEMATICS_PARTS\MS_MECHANICAL_Library.schlib; Mfr_name: KEYSTONE; Mfr_part_number: 29300; Mistral Part No: 160018020076-R; Package: SS; Part_type: MECHANICAL\SCREWS; Project: TI_MAXIE_CPB; RoHS: RoHS; Datasheet: Y:\MIS_DATABASE\DATASHEETS\MISC\MECHANICAL\29300.PDF
PCB1 = ACCESSORY_PROC062: ACCESSORIE AM65x EVM IDK BARE PCB; Chkd/date: MANIRAJA/230718; Crtd /date: MANIRAJA/230718; Mfr_name: TEXAS INSTRUMENTS; Mfr_part_number: PROC064; Mistral Part No: FY180646000203; Part_type: ACCESSORIES; Project: TI_MAXIE_CPB

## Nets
DGND: C1.2 C2.2 C3.2 C4.2 C6.2 C7.2 C8.2 C9.2 C14.2 C15.2 C16.2 C17.2 C18.2 C25.2 C26.2 C27.2 C31.2 C32.2 C33.2 C34.2 C35.2 C36.2 C37.2 C106.2 C107.2 C108.2 C122.2 C123.2 C127.2 C128.2 C129.2 C130.2 C131.2 C132.2 C133.2 C134.2 C135.2 C136.2 C137.2 J1.B10(GND) J5.17 J5.29 J5.30 Q1.2(S) Q2.2(S) Q6.2(S) Q8.2(S) Q9.2(S) Q10.2(S) Q12.2(S) Q13.2(S) Q14.2(S) Q18.2(S) Q19.2(S) R27.2 R28.2 R58.2 R62.2 R64.1 R66.1 R88.1 R209.1 R210.1 R215.1 R216.1 R220.2 R229.1 R230.1 R231.1 R238.1 R242.1 R244.1 R257.1 R392.2 R393.2 R394.2 R395.2 R396.2 R409.2 R414.2 R418.2 R421.2 R423.2 R425.2 R427.2 R429.2 U1.2(GND) U7.65(EP) U45.4(GND) U46.4(GND) U47.28(GND) U47.29(EP) U51.8(~{G}) U51.16(GND) U64.3(GND) ; also on sheet 4 5 6 7 12
VCC_1V1: C26.1 C32.1 C33.1 C37.1 C123.1 C128.1 C129.1 C130.1 C132.1 C135.1 U7.8(VDD1P1) U7.29(VDD1P1) U7.42(VDD1P1) U7.58(VDD1P1) ; also on sheet 4 5 6 7
VCC_1V8: C6.1 C27.1 C34.1 C36.1 C122.1 C131.1 C136.1 C137.1 FL2.1 R1.1 R56.1 R60.1 R67.2 R68.2 R69.2 R389.2 R408.2 R412.1 R417.2 R422.2 R424.1 R426.1 R428.2 R430.1 U1.1(VCCA) U7.23(VDDIO) U7.41(VDDIO) U7.57(VDDIO) ; also on sheet 4 5 6 7 12
VCC_2V5: C31.1 C35.1 C127.1 C133.1 C134.1 U7.4(VDDA2P5) U7.12(VDDA2P5) ; also on sheet 4 5 6 7
VCC_3V3: C1.1 C3.1 C25.1 C106.1 R63.1 R65.1 R70.1 R85.1 R93.1 R96.1 R211.1 R218.2 R224.2 R226.1 R256.2 R261.2 R262.2 R460.2 SW1.C1 SW1.C2 U45.1(VCCA) U46.8(VDD) U51.1(VCC) U64.5(VCC) ; also on sheet 4 5 6 7 12
VCC_5V0: C2.1 C4.1 C107.1 C108.1 J5.27 J5.28 R16.2 R137.1 R138.1 R139.1 R140.1 R141.1 R142.1 R143.1 R144.1 U1.6(VCCB) U45.8(VCCB) U47.15(VCC) ; also on sheet 4 12
DRAIN0: J5.19 LD7.1(CATHODE) U51.3(DRAIN0)
DRAIN1: J5.20 LD8.1(CATHODE) U51.4(DRAIN1)
DRAIN2: J5.21 LD9.1(CATHODE) U51.5(DRAIN2)
DRAIN3: J5.22 LD10.1(CATHODE) U51.6(DRAIN3)
DRAIN4: J5.23 LD11.1(CATHODE) U51.11(DRAIN4)
DRAIN5: J5.24 LD12.1(CATHODE) U51.12(DRAIN5)
DRAIN6: J5.25 LD13.1(CATHODE) U51.13(DRAIN6)
DRAIN7: J5.26 LD14.1(CATHODE) U51.14(DRAIN7)
ETH2/3_INTn: U7.60(INT/PWDN) ; also on sheet 4 7
ETH2/3_MDC: U7.20(MDC) ; also on sheet 4 7
ETH2/3_MDIO: U7.21(MDIO) ; also on sheet 4 7
ETH2/3_RESETn: U7.59(RESET_N) ; also on sheet 7
ETH3_CLK: U7.19(X_I) ; also on sheet 4
ETH3_CLK_OUT: TP9.1(TP) U7.22(CLK_OUT)
ETH3_D0M: J1.B2(TD1-_2) U7.3(TD_M_A)
ETH3_D0P: J1.B1(TD1+_2) U7.2(TD_P_A)
ETH3_D1M: J1.B4(TD2-_2) U7.6(TD_M_B)
ETH3_D1P: J1.B3(TD2+_2) U7.5(TD_P_B)
ETH3_D2M: J1.B6(TD3-_2) U7.11(TD_M_C)
ETH3_D2P: J1.B5(TD3+_2) U7.10(TD_P_C)
ETH3_D3M: J1.B8(TD4-_2) U7.14(TD_M_D)
ETH3_D3P: J1.B7(TD4+_2) U7.13(TD_P_D)
ETH3_LED1: J1.B11 Q12.3(D)
ETH3_LED2: J1.B13 Q8.3(D) R224.1
ETH3_LED3: J1.B14 Q6.3(D) R218.1
ETH3_LED_1000: R213.2 R451.2 U7.62(LED_1)
ETH3_LED_ACT: R233.1 U7.61(LED_2)
ETH3_LED_LINK: R427.1 R430.2 U7.63(LED_0) ; also on sheet 4
ETH3_MII_COL: R227.2 U7.55(COL/GPIO)
ETH3_MII_CRS: R425.1 R426.2 U7.56(CS/GPIO)
ETH3_MII_RXER: U7.54(RX_ER/GPIO) ; also on sheet 4
ETH3_MII_TXC_R: R459.2 U7.30(TX_CLK)
ETH3_RGMII_RD0: R60.2 R62.1 U7.44(RX_D0) ; also on sheet 4
ETH3_RGMII_RD1: U7.45(RX_D1) ; also on sheet 4
ETH3_RGMII_RD2: R56.2 R58.1 U7.46(RX_D2) ; also on sheet 4
ETH3_RGMII_RD3: U7.47(RX_D3) ; also on sheet 4
ETH3_RGMII_RD4: R450.2 U7.48(RX_D4/GPIO)
ETH3_RGMII_RD5: R412.2 R414.1 U7.49(RX_D5/GPIO)
ETH3_RGMII_RD6: R420.2 U7.50(RX_D6/GPIO)
ETH3_RGMII_RD7: R423.1 R424.2 U7.51(RX_D7/GPIO)
ETH3_RGMII_RX_CTL: R421.1 R422.1 U7.53(RX_DV/RX_CTRL) ; also on sheet 4
ETH3_RGMII_RXC: U7.43(RX_CLK) ; also on sheet 4
ETH3_RGMII_TD0: R397.1 R399.1 ; also on sheet 4
ETH3_RGMII_TD0_R: R397.2 R406.2 U7.38(TX_D0)
ETH3_RGMII_TD1: R398.1 R400.1 ; also on sheet 4
ETH3_RGMII_TD1_R: R398.2 R399.2 U7.37(TX_D1)
ETH3_RGMII_TD2: R401.1 R403.1 ; also on sheet 4
ETH3_RGMII_TD2_R: R400.2 R401.2 U7.36(TX_D2)
ETH3_RGMII_TD3: R402.1 R405.1 ; also on sheet 4
ETH3_RGMII_TD3_R: R402.2 R403.2 U7.35(TX_D3)
ETH3_RGMII_TD4_R: R392.1 U7.34(TX_D4)
ETH3_RGMII_TD5_R: R393.1 U7.33(TX_D5)
ETH3_RGMII_TD6_R: R395.1 U7.32(TX_D6)
ETH3_RGMII_TD7_R: R394.1 U7.31(TX_D7)
ETH3_RGMII_TX_CTL: R404.1 R406.1 ; also on sheet 4
ETH3_RGMII_TX_CTL_R: R404.2 R405.2 U7.52(TX_EN/TX_CTRL)
ETH3_RGMII_TXC: R458.1 R459.1 ; also on sheet 4
ETH3_RGMII_TXC_R: R458.2 U7.40(GTX_CLK)
ETH_EARTH: J1.SH4 ; also on sheet 6
ETH_LED1: Q9.1(G) R229.2 ; also on sheet 4
ETH_LED2: Q1.1(G) R64.2 ; also on sheet 4
ETH_LED3: Q10.1(G) R230.2 ; also on sheet 4
ETH_LED4: Q13.1(G) R231.2 ; also on sheet 4
ETH_LED5: Q14.1(G) R238.2 ; also on sheet 4
ETH_LED6: Q2.1(G) R88.2 ; also on sheet 4
ETH_LED7: Q18.1(G) R242.2 ; also on sheet 4
ETH_LED8: Q19.1(G) R244.2 ; also on sheet 4
IDK_I2C_SCL: U46.6(SCL) U51.15(SCL) ; also on sheet 4
IDK_I2C_SDA: U46.7(SDA) U51.2(SDA) ; also on sheet 4
IDK_IOEXP_LDn_1V8: U1.3(A) ; also on sheet 4
IDK_SPI_CLK_3V3: U45.3(A2) ; also on sheet 4
IDK_SPI_CSn_3V3: R460.1 U45.2(A1) U64.1(~{OE}) ; also on sheet 4
IDK_SPI_MISO_3V3: U64.4(Y) ; also on sheet 4
INDUS_INPUT0: J5.1 R37.2
INDUS_INPUT1: J5.3 R36.2
INDUS_INPUT2: J5.5 R35.2
INDUS_INPUT3: J5.7 R34.2
INDUS_INPUT4: J5.9 R33.2
INDUS_INPUT5: J5.11 R3.2
INDUS_INPUT6: J5.13 R4.2
INDUS_INPUT7: J5.15 R5.2
IOEXP_LDn_5V0: U1.4(B) U47.26(~{LD})
IOEXP_SPI_CLK_5V0: U45.6(B2) U47.25(CLK)
IOEXP_SPI_CSn_5V0: U45.7(B1) U47.24(~{CE})
IOEXP_SPI_DB0_5V0: R28.1 U47.1(DB0)
IOEXP_SPI_DB1_5V0: R220.1 U47.2(DB1)
IOEXP_SPI_MISO_5V0: U47.23(SOP) U64.2(A)
IOEXP_SPI_MOSI_5V0: R16.1 U47.27(SIP)
IOEXP_SPI_RLIM_5V0: R27.1 U47.13(RLIM)
LED1: LD1.3 Q9.3(D)
LED2: LD1.4 Q1.3(D)
LED3: LD2.1(CATHODE) Q10.3(D)
LED4: LD3.1(CATHODE) Q13.3(D)
LED5: LD4.3 Q14.3(D)
LED6: LD4.4 Q2.3(D)
LED7: LD5.1(CATHODE) Q18.3(D)
LED8: LD6.1(CATHODE) Q19.3(D)
R_SW1: R216.2 SW1.1 U46.1(P0)
R_SW2: R210.2 SW1.2 U46.2(P1)
R_SW4: R215.2 SW1.4 U46.3(P2)
R_SW8: R209.2 SW1.8 U46.5(P3)
N16788469: J1.B12 R226.2
N16789697: Q12.1(G) R233.2
N16789720: Q8.1(G) R227.1
N16789777: Q6.1(G) R213.1
N16789822: FL2.2 J1.B9(VCC)
N16796360: LD1.1 LD1.2 R63.2
N16796372: LD2.2(ANODE) R65.2
N16796398: LD3.2(ANODE) R70.2
N16796416: LD4.1 LD4.2 R85.2
N16796430: LD5.2(ANODE) R93.2
N16796442: LD6.2(ANODE) R96.2
N16816677: R256.1 R257.2 U51.7(A2)
N16816685: R262.1 U51.10(A1)
N16816697: R261.1 U51.9(A0)
N16823059: C7.1 R3.1 U47.18(IP5)
N16823111: C8.1 R4.1 U47.20(IP6)
N16823216: C9.1 R5.1 U47.22(IP7)
N16823285: C14.1 R33.1 U47.11(IP4)
N16823415: C15.1 R34.1 U47.9(IP3)
N16823453: C16.1 R35.1 U47.7(IP2)
N16823473: C17.1 R36.1 U47.5(IP1)
N16823493: C18.1 R37.1 U47.3(IP0)
N16928826: TP1.1(TP) U47.16(~{HOT})
N16980752: LD7.2(ANODE) R137.2
N16982224: LD8.2(ANODE) R138.2
N16982264: LD9.2(ANODE) R139.2
N16982304: LD10.2(ANODE) R140.2
N16982344: LD11.2(ANODE) R144.2
N16982384: LD12.2(ANODE) R143.2
N16982472: LD13.2(ANODE) R142.2
N16982512: LD14.2(ANODE) R141.2
N17056189: R211.2 U45.5(DIR)
N17057104: R1.2 U1.5(DIR)
N17675428: R66.2 U7.15(RBIAS)
N17675949: TP8.1(TP) U7.17(VDDA1P8) U7.64(VDDA1P8)
N17677025: R67.1 U7.27(JTAG_TMS)
N17677027: R68.1 U7.28(JTAG_TDI)
N17677029: R69.1 U7.24(JTAG_TRSTN)
N17677232: R389.1 U7.25(JTAG_CLK)
N17682457: R396.1 U7.39(TX_ER)
N17683493: R408.1 R409.1 R450.1
N17683655: R417.1 R418.1 R420.1
N17683783: R428.1 R429.1 R451.1

Not connected (* = marked no-connect by the designer): J1 SH3*; J5 2* 4* 6* 8* 10* 12* 14* 16* 18*; U7 1(RESERVED4)* 7(RESERVED3)* 9(RESERVED2)* 16(RESERVED1)* 18(X_O)* 26(JTAG_TDO)*; U47 4(RE0)* 6(RE1)* 8(RE2)* 10(RE3)* 12(RE4)* 14(NC)* 17(RE5)* 19(RE6)* 21(RE7)*

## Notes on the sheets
sheet 8
- STRAPPING RESISTORS
- RGMII Mode:
  Mount : R397, R398, R401, R402, R404,R458
  Unmount : R399, R400, R403, R405, R406, R420, R450, R451,R459
- MII Mode:
  Mount : R399, R400, R403, R405, R406, R420, R450, R451,R459
  Unmount : R397, R398, R401, R402, R404,R458
- PHY ADD = 00011
- Auto_neg =Enabled
  ANEGsel 10/100/1000
sheet 10
- HARDWARE SCHEMATICS
- ASSEMBLY NOTES
- SCREWS
- FIDUCIALS
- 1. All MSL components should be baked as per JEDEC standard.
  2. PCB should be baked at 120 degree for 8 hours.
  3. Board assembly must comply with workmanship standards.
  IPC-A-610 Class 2, unless otherwise specified.
  4. These assemblies are ESD sensitive, ESD precautions
  shall be observed.
  5. These assemblies must be clean and free from flux and
  all contaminants. Use of no clean flux is not acceptable.
  6. Provide serial numbers to the assembled boards for identification.
  7. The assembled board are wrapped in ESD Covers(individual) and
  packed securely before shipment.
- WASHER's
- These mechanicals will be used to secure this board to PROC062
- LABELS
- BARE PCB
- LOGOs
- Board Serial No.
- Assembly Revision
- Texas Intruments
- For Evaluation only; not FCC approved for resale
- CE Mark
- WEEE Mark
sheet 11
- I2C ADDRESS: 0x41
- INDUS_INPUTx are input with
  Von(1) = 8.2V and Voff(0) = 7.3V
- DRAINx are open drain output with
  VDS(MAX) = 8V and IDS (MAX) = 80mA
- I2C ADDRESS: 0x63
